VERSION 5.7 ;
  NOWIREEXTENSIONATPIN ON ;
  DIVIDERCHAR "/" ;
  BUSBITCHARS "[]" ;
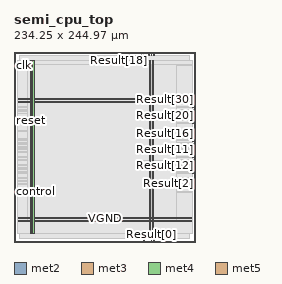
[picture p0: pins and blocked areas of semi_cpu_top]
MACRO semi_cpu_top
  CLASS BLOCK ;
  FOREIGN semi_cpu_top ;
  ORIGIN 0.000 0.000 ;
  SIZE 234.250 BY 244.970 ;
  PIN Result[0]
    DIRECTION OUTPUT ;
    USE SIGNAL ;
    ANTENNADIFFAREA 0.445500 ;
    PORT
      LAYER met2 ;
        RECT 177.190 0.000 177.470 4.000 ;
    END
  END Result[0]
  PIN Result[10]
    DIRECTION OUTPUT ;
    USE SIGNAL ;
    ANTENNADIFFAREA 0.445500 ;
    PORT
      LAYER met3 ;
        RECT 230.250 95.240 234.250 95.840 ;
    END
  END Result[10]
  PIN Result[11]
    DIRECTION OUTPUT ;
    USE SIGNAL ;
    ANTENNADIFFAREA 0.445500 ;
    PORT
      LAYER met3 ;
        RECT 230.250 119.040 234.250 119.640 ;
    END
  END Result[11]
  PIN Result[12]
    DIRECTION OUTPUT ;
    USE SIGNAL ;
    ANTENNADIFFAREA 0.445500 ;
    PORT
      LAYER met3 ;
        RECT 230.250 108.840 234.250 109.440 ;
    END
  END Result[12]
  PIN Result[13]
    DIRECTION OUTPUT ;
    USE SIGNAL ;
    ANTENNADIFFAREA 0.445500 ;
    PORT
      LAYER met3 ;
        RECT 230.250 115.640 234.250 116.240 ;
    END
  END Result[13]
  PIN Result[14]
    DIRECTION OUTPUT ;
    USE SIGNAL ;
    ANTENNADIFFAREA 0.445500 ;
    PORT
      LAYER met3 ;
        RECT 230.250 125.840 234.250 126.440 ;
    END
  END Result[14]
  PIN Result[15]
    DIRECTION OUTPUT ;
    USE SIGNAL ;
    ANTENNADIFFAREA 0.445500 ;
    PORT
      LAYER met3 ;
        RECT 230.250 122.440 234.250 123.040 ;
    END
  END Result[15]
  PIN Result[16]
    DIRECTION OUTPUT ;
    USE SIGNAL ;
    ANTENNADIFFAREA 0.445500 ;
    PORT
      LAYER met3 ;
        RECT 230.250 129.240 234.250 129.840 ;
    END
  END Result[16]
  PIN Result[17]
    DIRECTION OUTPUT ;
    USE SIGNAL ;
    ANTENNADIFFAREA 0.445500 ;
    PORT
      LAYER met3 ;
        RECT 230.250 132.640 234.250 133.240 ;
    END
  END Result[17]
  PIN Result[18]
    DIRECTION OUTPUT ;
    USE SIGNAL ;
    ANTENNADIFFAREA 0.795200 ;
    PORT
      LAYER met2 ;
        RECT 135.330 240.970 135.610 244.970 ;
    END
  END Result[18]
  PIN Result[19]
    DIRECTION OUTPUT ;
    USE SIGNAL ;
    ANTENNADIFFAREA 0.445500 ;
    PORT
      LAYER met3 ;
        RECT 230.250 142.840 234.250 143.440 ;
    END
  END Result[19]
  PIN Result[1]
    DIRECTION OUTPUT ;
    USE SIGNAL ;
    ANTENNADIFFAREA 0.445500 ;
    PORT
      LAYER met2 ;
        RECT 180.410 0.000 180.690 4.000 ;
    END
  END Result[1]
  PIN Result[20]
    DIRECTION OUTPUT ;
    USE SIGNAL ;
    ANTENNADIFFAREA 0.445500 ;
    PORT
      LAYER met3 ;
        RECT 230.250 153.040 234.250 153.640 ;
    END
  END Result[20]
  PIN Result[21]
    DIRECTION OUTPUT ;
    USE SIGNAL ;
    ANTENNADIFFAREA 0.795200 ;
    PORT
      LAYER met2 ;
        RECT 148.210 240.970 148.490 244.970 ;
    END
  END Result[21]
  PIN Result[22]
    DIRECTION OUTPUT ;
    USE SIGNAL ;
    ANTENNADIFFAREA 0.445500 ;
    PORT
      LAYER met3 ;
        RECT 230.250 166.640 234.250 167.240 ;
    END
  END Result[22]
  PIN Result[23]
    DIRECTION OUTPUT ;
    USE SIGNAL ;
    ANTENNADIFFAREA 0.445500 ;
    PORT
      LAYER met3 ;
        RECT 230.250 170.040 234.250 170.640 ;
    END
  END Result[23]
  PIN Result[24]
    DIRECTION OUTPUT ;
    USE SIGNAL ;
    ANTENNADIFFAREA 0.795200 ;
    PORT
      LAYER met2 ;
        RECT 173.970 240.970 174.250 244.970 ;
    END
  END Result[24]
  PIN Result[25]
    DIRECTION OUTPUT ;
    USE SIGNAL ;
    ANTENNADIFFAREA 0.795200 ;
    PORT
      LAYER met2 ;
        RECT 177.190 240.970 177.470 244.970 ;
    END
  END Result[25]
  PIN Result[26]
    DIRECTION OUTPUT ;
    USE SIGNAL ;
    ANTENNADIFFAREA 0.795200 ;
    PORT
      LAYER met2 ;
        RECT 180.410 240.970 180.690 244.970 ;
    END
  END Result[26]
  PIN Result[27]
    DIRECTION OUTPUT ;
    USE SIGNAL ;
    ANTENNADIFFAREA 0.795200 ;
    PORT
      LAYER met2 ;
        RECT 167.530 240.970 167.810 244.970 ;
    END
  END Result[27]
  PIN Result[28]
    DIRECTION OUTPUT ;
    USE SIGNAL ;
    ANTENNADIFFAREA 0.795200 ;
    PORT
      LAYER met2 ;
        RECT 170.750 240.970 171.030 244.970 ;
    END
  END Result[28]
  PIN Result[29]
    DIRECTION OUTPUT ;
    USE SIGNAL ;
    ANTENNADIFFAREA 0.795200 ;
    PORT
      LAYER met2 ;
        RECT 164.310 240.970 164.590 244.970 ;
    END
  END Result[29]
  PIN Result[2]
    DIRECTION OUTPUT ;
    USE SIGNAL ;
    ANTENNADIFFAREA 0.445500 ;
    PORT
      LAYER met3 ;
        RECT 230.250 74.840 234.250 75.440 ;
    END
  END Result[2]
  PIN Result[30]
    DIRECTION OUTPUT ;
    USE SIGNAL ;
    ANTENNADIFFAREA 0.445500 ;
    PORT
      LAYER met3 ;
        RECT 230.250 173.440 234.250 174.040 ;
    END
  END Result[30]
  PIN Result[31]
    DIRECTION OUTPUT ;
    USE SIGNAL ;
    ANTENNADIFFAREA 0.795200 ;
    PORT
      LAYER met2 ;
        RECT 151.430 240.970 151.710 244.970 ;
    END
  END Result[31]
  PIN Result[3]
    DIRECTION OUTPUT ;
    USE SIGNAL ;
    ANTENNADIFFAREA 0.445500 ;
    PORT
      LAYER met2 ;
        RECT 167.530 0.000 167.810 4.000 ;
    END
  END Result[3]
  PIN Result[4]
    DIRECTION OUTPUT ;
    USE SIGNAL ;
    ANTENNADIFFAREA 0.445500 ;
    PORT
      LAYER met3 ;
        RECT 230.250 78.240 234.250 78.840 ;
    END
  END Result[4]
  PIN Result[5]
    DIRECTION OUTPUT ;
    USE SIGNAL ;
    ANTENNADIFFAREA 0.445500 ;
    PORT
      LAYER met3 ;
        RECT 230.250 105.440 234.250 106.040 ;
    END
  END Result[5]
  PIN Result[6]
    DIRECTION OUTPUT ;
    USE SIGNAL ;
    ANTENNADIFFAREA 0.445500 ;
    PORT
      LAYER met3 ;
        RECT 230.250 88.440 234.250 89.040 ;
    END
  END Result[6]
  PIN Result[7]
    DIRECTION OUTPUT ;
    USE SIGNAL ;
    ANTENNADIFFAREA 0.445500 ;
    PORT
      LAYER met3 ;
        RECT 230.250 81.640 234.250 82.240 ;
    END
  END Result[7]
  PIN Result[8]
    DIRECTION OUTPUT ;
    USE SIGNAL ;
    ANTENNADIFFAREA 0.445500 ;
    PORT
      LAYER met3 ;
        RECT 230.250 91.840 234.250 92.440 ;
    END
  END Result[8]
  PIN Result[9]
    DIRECTION OUTPUT ;
    USE SIGNAL ;
    ANTENNADIFFAREA 0.445500 ;
    PORT
      LAYER met3 ;
        RECT 230.250 98.640 234.250 99.240 ;
    END
  END Result[9]
  PIN VGND
    DIRECTION INOUT ;
    USE GROUND ;
    PORT
      LAYER met4 ;
        RECT 24.340 10.640 25.940 234.160 ;
    END
    PORT
      LAYER met4 ;
        RECT 177.940 10.640 179.540 234.160 ;
    END
    PORT
      LAYER met5 ;
        RECT 5.280 30.030 228.860 31.630 ;
    END
    PORT
      LAYER met5 ;
        RECT 5.280 183.210 228.860 184.810 ;
    END
  END VGND
  PIN VPWR
    DIRECTION INOUT ;
    USE POWER ;
    PORT
      LAYER met4 ;
        RECT 21.040 10.640 22.640 234.160 ;
    END
    PORT
      LAYER met4 ;
        RECT 174.640 10.640 176.240 234.160 ;
    END
    PORT
      LAYER met5 ;
        RECT 5.280 26.730 228.860 28.330 ;
    END
    PORT
      LAYER met5 ;
        RECT 5.280 179.910 228.860 181.510 ;
    END
  END VPWR
  PIN clk
    DIRECTION INPUT ;
    USE SIGNAL ;
    ANTENNAGATEAREA 0.852000 ;
    PORT
      LAYER met3 ;
        RECT 0.000 227.840 4.000 228.440 ;
    END
  END clk
  PIN control
    DIRECTION INPUT ;
    USE SIGNAL ;
    ANTENNAGATEAREA 0.247500 ;
    PORT
      LAYER met3 ;
        RECT 0.000 64.640 4.000 65.240 ;
    END
  END control
  PIN reset
    DIRECTION INPUT ;
    USE SIGNAL ;
    ANTENNAGATEAREA 0.622500 ;
    PORT
      LAYER met3 ;
        RECT 0.000 156.440 4.000 157.040 ;
    END
  END reset
  OBS
      LAYER nwell ;
        RECT 5.330 10.795 228.810 234.005 ;
      LAYER li1 ;
        RECT 5.520 10.795 228.620 234.005 ;
      LAYER met1 ;
        RECT 5.520 10.640 228.620 234.160 ;
      LAYER met2 ;
        RECT 7.000 240.690 135.050 240.970 ;
        RECT 135.890 240.690 147.930 240.970 ;
        RECT 148.770 240.690 151.150 240.970 ;
        RECT 151.990 240.690 164.030 240.970 ;
        RECT 164.870 240.690 167.250 240.970 ;
        RECT 168.090 240.690 170.470 240.970 ;
        RECT 171.310 240.690 173.690 240.970 ;
        RECT 174.530 240.690 176.910 240.970 ;
        RECT 177.750 240.690 180.130 240.970 ;
        RECT 180.970 240.690 226.690 240.970 ;
        RECT 7.000 4.280 226.690 240.690 ;
        RECT 7.000 4.000 167.250 4.280 ;
        RECT 168.090 4.000 176.910 4.280 ;
        RECT 177.750 4.000 180.130 4.280 ;
        RECT 180.970 4.000 226.690 4.280 ;
      LAYER met3 ;
        RECT 4.000 228.840 230.250 234.085 ;
        RECT 4.400 227.440 230.250 228.840 ;
        RECT 4.000 174.440 230.250 227.440 ;
        RECT 4.000 173.040 229.850 174.440 ;
        RECT 4.000 171.040 230.250 173.040 ;
        RECT 4.000 169.640 229.850 171.040 ;
        RECT 4.000 167.640 230.250 169.640 ;
        RECT 4.000 166.240 229.850 167.640 ;
        RECT 4.000 157.440 230.250 166.240 ;
        RECT 4.400 156.040 230.250 157.440 ;
        RECT 4.000 154.040 230.250 156.040 ;
        RECT 4.000 152.640 229.850 154.040 ;
        RECT 4.000 143.840 230.250 152.640 ;
        RECT 4.000 142.440 229.850 143.840 ;
        RECT 4.000 133.640 230.250 142.440 ;
        RECT 4.000 132.240 229.850 133.640 ;
        RECT 4.000 130.240 230.250 132.240 ;
        RECT 4.000 128.840 229.850 130.240 ;
        RECT 4.000 126.840 230.250 128.840 ;
        RECT 4.000 125.440 229.850 126.840 ;
        RECT 4.000 123.440 230.250 125.440 ;
        RECT 4.000 122.040 229.850 123.440 ;
        RECT 4.000 120.040 230.250 122.040 ;
        RECT 4.000 118.640 229.850 120.040 ;
        RECT 4.000 116.640 230.250 118.640 ;
        RECT 4.000 115.240 229.850 116.640 ;
        RECT 4.000 109.840 230.250 115.240 ;
        RECT 4.000 108.440 229.850 109.840 ;
        RECT 4.000 106.440 230.250 108.440 ;
        RECT 4.000 105.040 229.850 106.440 ;
        RECT 4.000 99.640 230.250 105.040 ;
        RECT 4.000 98.240 229.850 99.640 ;
        RECT 4.000 96.240 230.250 98.240 ;
        RECT 4.000 94.840 229.850 96.240 ;
        RECT 4.000 92.840 230.250 94.840 ;
        RECT 4.000 91.440 229.850 92.840 ;
        RECT 4.000 89.440 230.250 91.440 ;
        RECT 4.000 88.040 229.850 89.440 ;
        RECT 4.000 82.640 230.250 88.040 ;
        RECT 4.000 81.240 229.850 82.640 ;
        RECT 4.000 79.240 230.250 81.240 ;
        RECT 4.000 77.840 229.850 79.240 ;
        RECT 4.000 75.840 230.250 77.840 ;
        RECT 4.000 74.440 229.850 75.840 ;
        RECT 4.000 65.640 230.250 74.440 ;
        RECT 4.400 64.240 230.250 65.640 ;
        RECT 4.000 10.715 230.250 64.240 ;
      LAYER met4 ;
        RECT 16.855 27.375 20.640 228.305 ;
        RECT 23.040 27.375 23.940 228.305 ;
        RECT 26.340 27.375 174.240 228.305 ;
        RECT 176.640 27.375 177.540 228.305 ;
        RECT 179.940 27.375 209.465 228.305 ;
      LAYER met5 ;
        RECT 159.740 102.900 194.460 104.500 ;
  END
END semi_cpu_top
END LIBRARY

